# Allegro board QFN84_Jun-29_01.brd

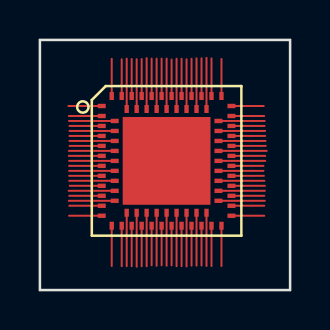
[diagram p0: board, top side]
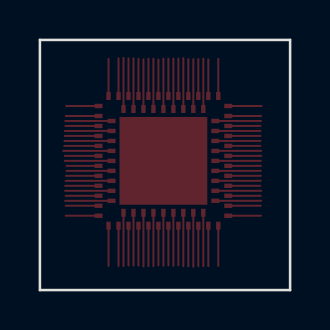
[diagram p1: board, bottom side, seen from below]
Outline 12.54 x 12.54 mm; copper layers: TOP, BOTTOM. Coordinates in mm from the lower left corner of the outline.
Outline path: 0,12.54 0,0 12.54,0 12.54,12.54 0,12.54

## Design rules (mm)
net group 3.5MILS: nets B1 B2 B3 B4 B5 B6 B7 B8 B9 B10 B11 B12 B13 B14 B15 B16 B17 B18 B19 B20 B21 B22 B23 B24 B25 B26 B27 B28 B29 B30 B31 B32 B33 B34 B35 B36
net group 5MILS: nets A1 A2 A3 A4 A5 A6 A7 A8 A9 A10 A11 A12 A13 A14 A15 A16 A17 A18 A19 A20 A21 A22 A23 A24 A25 A26 A27 A28 A29 A30 A31 A32 A33 A34 A35 A36 A37 A38 A39 A40 A41 A42 A43 A44 A45 A46 A47 A48

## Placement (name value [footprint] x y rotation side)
U1  -  [QFN84]  6.35 6.48 0 top

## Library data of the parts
U1 = QFN84

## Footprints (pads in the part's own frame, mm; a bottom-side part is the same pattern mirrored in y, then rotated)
QFN84
  rect 4.4x4.4 smd: 42(0,0)
  rect 0.4x0.22 smd: A1(-3.25,2.75) A2(-3.25,2.25) A3(-3.25,1.75) A4(-3.25,1.25) A5(-3.25,0.75) A6(-3.25,0.25) A7(-3.25,-0.25) A8(-3.25,-0.75) A9(-3.25,-1.25) A10(-3.25,-1.75) A11(-3.25,-2.25) A12(-3.25,-2.75) A25(3.25,-2.75) A26(3.25,-2.25) A27(3.25,-1.75) A28(3.25,-1.25) A29(3.25,-0.75) A30(3.25,-0.25) A31(3.25,0.25) A32(3.25,0.75) A33(3.25,1.25) A34(3.25,1.75) A35(3.25,2.25) A36(3.25,2.75) B1(-2.6,2) B2(-2.6,1.5) B3(-2.6,1) B4(-2.6,0.5) B5(-2.6,0) B6(-2.6,-0.5) B7(-2.6,-1) B8(-2.6,-1.5) B9(-2.6,-2) B19(2.6,-2) B20(2.6,-1.5) B21(2.6,-1) B22(2.6,-0.5) B23(2.6,0) B24(2.6,0.5) B25(2.6,1) B26(2.6,1.5) B27(2.6,2)
  rect 0.22x0.4 smd: A13(-2.75,-3.25) A14(-2.25,-3.25) A15(-1.75,-3.25) A16(-1.25,-3.25) A17(-0.75,-3.25) A18(-0.25,-3.25) A19(0.25,-3.25) A20(0.75,-3.25) A21(1.25,-3.25) A22(1.75,-3.25) A23(2.25,-3.25) A24(2.75,-3.25) A37(2.75,3.25) A38(2.25,3.25) A39(1.75,3.25) A40(1.25,3.25) A41(0.75,3.25) A42(0.25,3.25) A43(-0.25,3.25) A44(-0.75,3.25) A45(-1.25,3.25) A46(-1.75,3.25) A47(-2.25,3.25) A48(-2.75,3.25) B10(-2,-2.6) B11(-1.5,-2.6) B12(-1,-2.6) B13(-0.5,-2.6) B14(0,-2.6) B15(0.5,-2.6) B16(1,-2.6) B17(1.5,-2.6) B18(2,-2.6) B28(2,2.6) B29(1.5,2.6) B30(1,2.6) B31(0.5,2.6) B32(0,2.6) B33(-0.5,2.6) B34(-1,2.6) B35(-1.5,2.6) B36(-2,2.6)

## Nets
A1: U1.A1
A2: U1.A2
A3: U1.A3
A4: U1.A4
A5: U1.A5
A6: U1.A6
A7: U1.A7
A8: U1.A8
A9: U1.A9
A10: U1.A10
A11: U1.A11
A12: U1.A12
A13: U1.A13
A14: U1.A14
A15: U1.A15
A16: U1.A16
A17: U1.A17
A18: U1.A18
A19: U1.A19
A20: U1.A20
A21: U1.A21
A22: U1.A22
A23: U1.A23
A24: U1.A24
A25: U1.A25
A26: U1.A26
A27: U1.A27
A28: U1.A28
A29: U1.A29
A30: U1.A30
A31: U1.A31
A32: U1.A32
A33: U1.A33
A34: U1.A34
A35: U1.A35
A36: U1.A36
A37: U1.A37
A38: U1.A38
A39: U1.A39
A40: U1.A40
A41: U1.A41
A42: U1.A42
A43: U1.A43
A44: U1.A44
A45: U1.A45
A46: U1.A46
A48: U1.A48
B1: U1.B1
B2: U1.B2
B3: U1.B3
B4: U1.B4
B5: U1.B5
B6: U1.B6
B7: U1.B7
B8: U1.B8
B9: U1.B9
B10: U1.B10
B11: U1.B11
B12: U1.B12
B13: U1.B13
B14: U1.B14
B15: U1.B15
B16: U1.B16
B17: U1.B17
B18: U1.B18
B19: U1.B19
B20: U1.B20
B21: U1.B21
B22: U1.B22
B23: U1.B23
B24: U1.B24
B25: U1.B25
B26: U1.B26
B27: U1.B27
B28: U1.B28
B29: U1.B29
B30: U1.B30
B31: U1.B31
B32: U1.B32
B33: U1.B33
B34: U1.B34
B35: U1.B35
B36: U1.B36

Pads without a net: U1 42 A47

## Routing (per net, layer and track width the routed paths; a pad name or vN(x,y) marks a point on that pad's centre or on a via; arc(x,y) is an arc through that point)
A1: length 1.7
  TOP w0.1: U1.A1 1.43,9.23
A2: length 1.6
  TOP w0.1: U1.A2 1.45,8.73
A3: length 1.6
  TOP w0.1: U1.A3 1.48,8.23
A4: length 1.6
  TOP w0.1: U1.A4 1.48,7.73
A5: length 1.6
  TOP w0.1: U1.A5 1.49,7.23
A6: length 1.7
  TOP w0.1: U1.A6 1.45,6.73
A7: length 1.6
  TOP w0.1: U1.A7 1.46,6.23
A8: length 1.6
  TOP w0.1: U1.A8 1.47,5.73
A9: length 1.6
  TOP w0.1: U1.A9 1.49,5.23
A10: length 1.6
  TOP w0.1: U1.A10 1.47,4.73
A11: length 1.6
  TOP w0.1: U1.A11 1.47,4.23
A12: length 1.6
  TOP w0.1: U1.A12 1.46,3.73
A13: length 2
  TOP w0.1: U1.A13 3.6,1.21
A14: length 2
  TOP w0.1: U1.A14 4.1,1.2
A15: length 2
  TOP w0.1: U1.A15 4.6,1.2
A16: length 2
  TOP w0.1: U1.A16 5.1,1.2
A17: length 2
  TOP w0.1: U1.A17 5.6,1.24
A18: length 2
  TOP w0.1: U1.A18 6.1,1.24
A19: length 2
  TOP w0.1: U1.A19 6.6,1.24
A20: length 2
  TOP w0.1: U1.A20 7.1,1.2
A21: length 2
  TOP w0.1: U1.A21 7.6,1.23
A22: length 2
  TOP w0.1: U1.A22 8.1,1.23
A23: length 2
  TOP w0.1: U1.A23 8.6,1.21
A24: length 2
  TOP w0.1: U1.A24 9.1,1.21
A25: length 1.6
  TOP w0.1: U1.A25 11.24,3.73
A26: length 1.6
  TOP w0.1: U1.A26 11.25,4.23
A27: length 1.6
  TOP w0.1: U1.A27 11.25,4.73
A28: length 1.7
  TOP w0.1: U1.A28 11.28,5.23
A29: length 1.6
  TOP w0.1: U1.A29 11.23,5.73
A30: length 1.6
  TOP w0.1: U1.A30 11.21,6.23
A31: length 1.7
  TOP w0.1: U1.A31 11.29,6.73
A32: length 1.7
  TOP w0.1: U1.A32 11.32,7.23
A33: length 1.7
  TOP w0.1: U1.A33 11.29,7.73
A34: length 1.7
  TOP w0.1: U1.A34 11.26,8.23
A35: length 1.6
  TOP w0.1: U1.A35 11.24,8.73
A36: length 1.6
  TOP w0.1: U1.A36 11.22,9.23
A37: length 1.9
  TOP w0.1: U1.A37 9.1,11.59
A38: length 1.9
  TOP w0.1: U1.A38 8.6,11.61
A39: length 1.9
  TOP w0.1: U1.A39 8.1,11.61
A40: length 1.9
  TOP w0.1: U1.A40 7.6,11.59
A41: length 1.9
  TOP w0.1: U1.A41 7.1,11.59
A42: length 1.8
  TOP w0.1: U1.A42 6.6,11.55
A43: length 1.9
  TOP w0.1: U1.A43 6.1,11.6
A44: length 1.9
  TOP w0.1: U1.A44 5.6,11.6
A45: length 1.9
  TOP w0.1: U1.A45 5.1,11.58
A46: length 1.9
  TOP w0.1: U1.A46 4.6,11.58
A48: length 1.9
  TOP w0.1: U1.A48 3.6,11.59
B1: length 2.3
  TOP w0.1: U1.B1 1.46,8.48
B2: length 2.3
  TOP w0.1: U1.B2 1.48,7.98
B3: length 2.3
  TOP w0.1: U1.B3 1.48,7.48
B4: length 2.3
  TOP w0.1: U1.B4 1.45,6.98
B5: length 2.3
  TOP w0.1: U1.B5 1.46,6.48
B6: length 2.3
  TOP w0.1: U1.B6 1.47,5.98
B7: length 2.3
  TOP w0.1: U1.B7 1.47,5.48
B8: length 2.3
  TOP w0.1: U1.B8 1.44,4.98
B9: length 2.3
  TOP w0.1: U1.B9 1.45,4.48
B10: length 2.7
  TOP w0.1: U1.B10 4.35,1.2
B11: length 2.7
  TOP w0.1: U1.B11 4.85,1.17
B12: length 2.7
  TOP w0.1: U1.B12 5.35,1.2
B13: length 2.7
  TOP w0.1: U1.B13 5.85,1.22
B14: length 2.7
  TOP w0.1: U1.B14 6.35,1.22
B15: length 2.7
  TOP w0.1: U1.B15 6.85,1.2
B16: length 2.7
  TOP w0.1: U1.B16 7.35,1.19
B17: length 2.6
  TOP w0.1: U1.B17 7.85,1.23
B18: length 2.7
  TOP w0.1: U1.B18 8.35,1.21
B19: length 2.3
  TOP w0.1: U1.B19 11.27,4.48
B20: length 2.3
  TOP w0.1: U1.B20 11.27,4.98
B21: length 2.3
  TOP w0.1: U1.B21 11.25,5.48
B22: length 2.3
  TOP w0.1: U1.B22 11.2,5.98
B23: length 2.3
  TOP w0.1: U1.B23 11.3,6.48
B24: length 2.4
  TOP w0.1: U1.B24 11.37,6.98
B25: length 2.4
  TOP w0.1: U1.B25 11.31,7.48
B26: length 2.3
  TOP w0.1: U1.B26 11.29,7.98
B27: length 2.3
  TOP w0.1: U1.B27 11.26,8.48
B28: length 2.6
  TOP w0.1: U1.B28 8.35,11.64
B29: length 2.5
  TOP w0.1: U1.B29 7.85,11.62
B30: length 2.5
  TOP w0.1: U1.B30 7.35,11.57
B31: length 2.5
  TOP w0.1: U1.B31 6.85,11.59
B32: length 2.5
  TOP w0.1: U1.B32 6.35,11.6
B33: length 2.5
  TOP w0.1: U1.B33 5.85,11.6
B34: length 2.5
  TOP w0.1: U1.B34 5.35,11.62
B35: length 2.5
  TOP w0.1: U1.B35 4.85,11.57
B36: length 2.5
  TOP w0.1: U1.B36 4.35,11.6
Net_86: length 1.8
  TOP w0.1: 4.1,9.73 4.1,11.57

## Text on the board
Ref Des/Silkscreen Top: 1.TRACE WIDTH     = 4 mils | 2.SPACING MINIMUM = 3.5 mils
